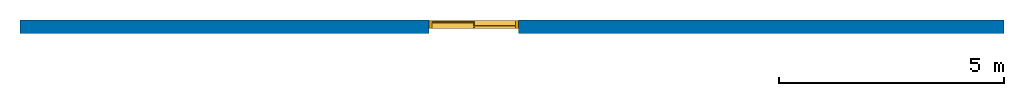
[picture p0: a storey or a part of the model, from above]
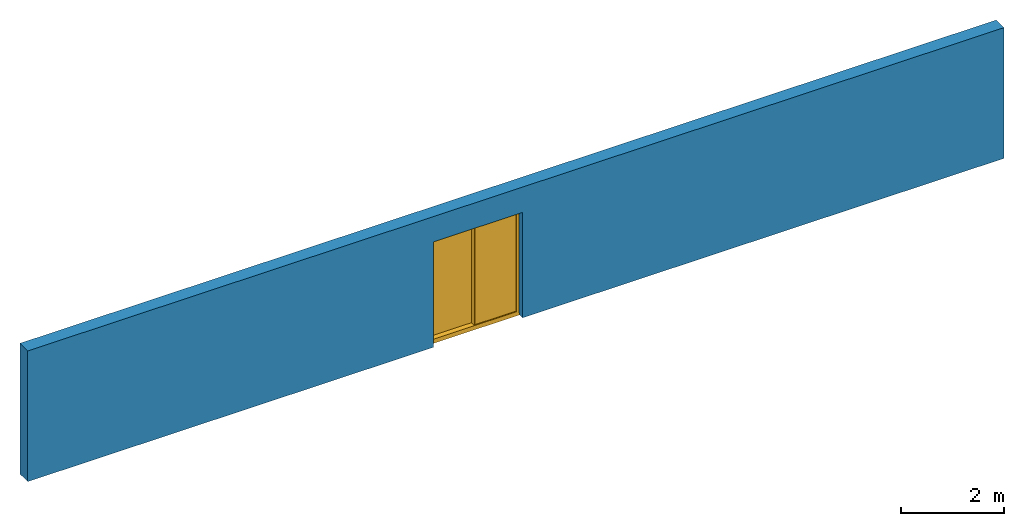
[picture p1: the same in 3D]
Properties of the parts of a building model (IFC2X3)

# File
Description: ViewDefinition [CoordinationView]
File name: Numero del progetto
Time: 2017-06-29T09:40:11
Written by: The EXPRESS Data Manager Version 5.01.0100.02.64mod : 6 Jun 2012
Made in: 20130308_1515(x64) - Exporter 2014.0.2013.0308 - Default UI
Comment: STEP Physical File produced by: The EXPRESS Data Manager Version 5.01.0100.02.64mod : 6 Jun 2012 * Module: EDMstepFileFactory/EDMstandAlone * Creation date: Thu Jun 29 09:40:11 2017 * Host: DELLATORRE-HP * Database: C:\Users\ILRAIA~1\AppData\Local\Temp\{E64BEFA2-977D-415D-8000-3A5D130E57A1}\ifc * Database version: 5507 * Database creation date: Thu Jun 29 09:40:09 2017 * Schema: IFC2X3 * Model: DataRepository.ifc * Model creation date: Thu Jun 29 09:40:09 2017 * Header model: DataRepository.ifc_HeaderModel * Header model creation date: Thu Jun 29 09:40:09 2017 * EDMuser: sdai-user * EDMgroup: sdai-group * License ID and type: 5605 : Permanent license. Expiry date: * EDMstepFileFactory options: 020000

# IfcProject, Numero del progetto
LongName: Nome; Phase: Stato del progetto

# IfcSite, Default
RefLatitude: 41, 47, 59, 997253; RefLongitude: 12, 36, 0, 1373; RefElevation: 0 m

# IfcBuilding
Pset_BuildingCommon - NumberOfStoreys: 1
Altro - Data di consegna del progetto: Data di consegna; Nome del progetto: Nome; Numero del progetto: Numero del progetto; Nome del cliente: proprietario; Stato del progetto: Stato del progetto

# IfcBuildingStorey, 0 - Piano Terra
LongName: 0 - Piano Terra; Elevation: 0 m
Vincoli - Base quota altimetrica: Punto base progetto; Prospetto: 0 m
Grafica - Colore: 0; Spessore di linea: 1; Simbolo: Estremità Livello: Triangolo; Simbolo a estremità 1 per default: no; Modello di linea: Tratto; Simbolo a estremità 2 per default: yes
Dimensioni - Altezza di calcolo: 0 m
Dati identità - Nome: 0 - Piano Terra; Strutturale: no; Piano edificio: yes

# IfcWallStandardCase: Muro di base:Generico - 30 cm, Muro di base:Generico - 30 cm:95119
In: 0 - Piano Terra
Type - PredefinedType: STANDARD; Material: Default - Muro 0.3 m
Type - Dati identità - Nota chiave: Mb/3
Type - Costruzione - Ripiegatura alle estremità: Nessuno; Funzione: Esterno; Larghezza: 0.3 m; Ripiegatura agli inserti: Non ripiegare
Type - Proprietà analitiche - Ruvidità: 3; Assorbimento: 0.7
Type - Grafica - Colore del retino a dettaglio basso: 0
Type - Materiali e finiture - Materiale strutturale: Default - Muro
Vincoli - Delimita il locale: yes; Offset base: 0 m; Vincolo di base: Livello: 0 - Piano Terra; Altezza non collegata: 3.1 m; Offset altezza: 0 m; L'altezza è associata: no; Vincolo di altezza: Livello: 1 - Piano Primo; La base è associata: no; Distanza estensione altezza: 0 m; Distanza estensione base: 0 m; Linea di ubicazione: Linea d'asse del muro; Relativo a massa: no
Dimensioni - Area: 62.89 m2; Volume: 18.867 m3; Lunghezza: 21.9 m
Strutturale - Attiva modello analitico: no; Strutturale: no; Utilizzo strutturale: Non portante
Fasi - Fase di creazione: Stato di Progetto
Pset_WallCommon - Reference: Generico - 30 cm; LoadBearing: no; ExtendToStructure: no; IsExternal: yes

# IfcWindow: 2 ante scorrevoli, Aluk_Infinium_2 ante:2 ante scorrevoli:98404
In: 0 - Piano Terra
Type - ParameterTakesPrecedence: no; Sizeable: no; Material: Aluk (IT), Vetro
OverallHeight: 2.5 m; OverallWidth: 2 m
Dimensioni - offset filo muro ext: 0.01 m; aria TOP: 0.01 m; aria DX: 0.005 m; aria SX: 0.005 m; Altezza: 2.5 m; Larghezza: 2 m
Dati identità - Contrassegno: 1; URL: http://infinium.aluk.com/it#!/cover; Titolo OmniClass: Windows; Contrassegno tipo: 28; Produttore: Aluk (IT); Numero OmniClass: 23.30.20.00
Vincoli - Livello: Livello: 0 - Piano Terra; Altezza soglia: 0 m; Altezza massima: 3.5 m; Larghezza massima: 6 m; Visibilità larghezza massima: no; Visibilità altezza massima: no
Fasi - Fase di creazione: Stato di Progetto
Altro - Altezza estremità: 2.5 m; Altezza di default del davanzale: 0 m
Pset_ManufacturerTypeInformation - Manufacturer: Aluk (IT)
Pset_WindowCommon - Reference: 2 ante scorrevoli; IsExternal: yes
Proprietà analitiche - Costruzione analitica: <Nessuno>
Materiali e finiture - Vetro: Vetro; Simboli: Simboli; Telaio: Aluk (IT)
Costruzione - Chiusura muro: Per host
Visibilità - ERRORE: no
